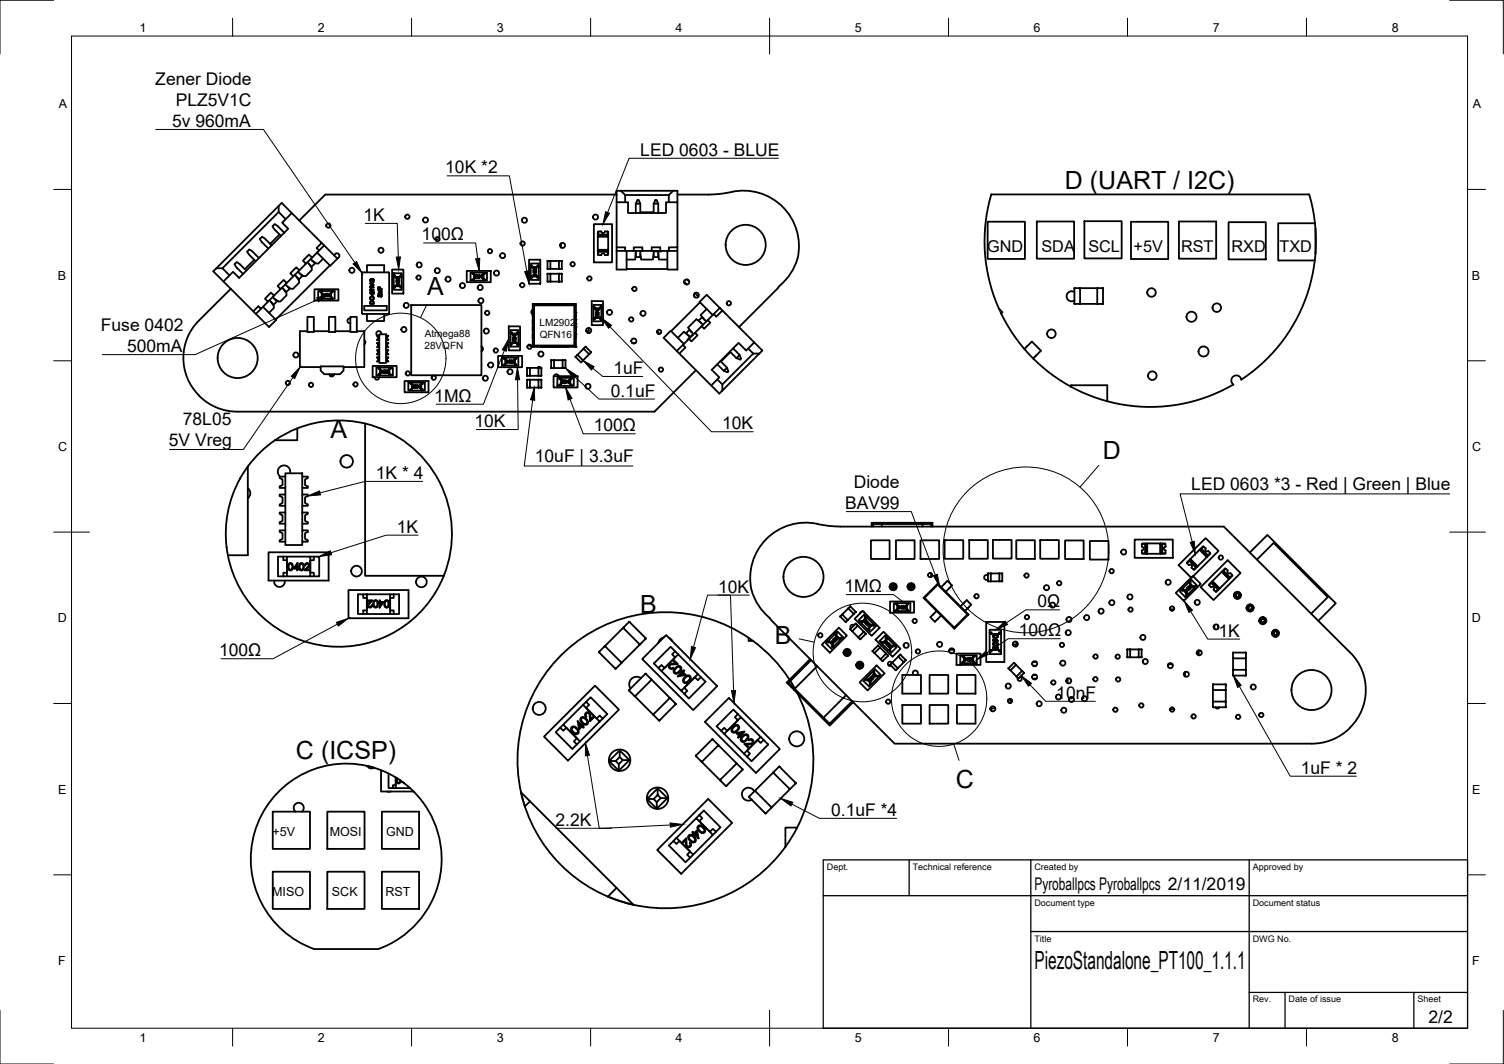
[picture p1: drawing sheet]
<svg xmlns="http://www.w3.org/2000/svg" width="420mm" height="297mm" viewBox="0 0 420 297" stroke-linecap="round" stroke-linejoin="round" font-family="sans-serif">
<defs><g id="words">
<g font-size="7">
<text x="297.5" y="52.8">D (UART / I2C)</text>
<text x="119.4" y="82.5">A</text>
<text x="92.3" y="122.4">A</text>
<text x="308.1" y="128">D</text>
<text x="178.8" y="171.2">B</text>
<text x="216.5" y="179.9">B</text>
<text x="82.7" y="212">C (ICSP)</text>
<text x="267" y="219.9">C</text>
<text x="289" y="270.6">PiezoStandalone_PT100_1.1.1</text>
</g>
<g font-size="4.9">
<text x="43.4" y="23.7">Zener Diode</text>
<text x="49.1" y="29.6">PLZ5V1C</text>
<text x="48.1" y="35.4">5v 960mA</text>
<text x="178.9" y="43.5">LED 0603 - BLUE</text>
<text x="124.4" y="48.4">10K *2</text>
<text x="101.5" y="61.7">1K</text>
<text x="117.8" y="67.1">100Ω</text>
<text x="28.2" y="92.5">Fuse 0402</text>
<text x="35.5" y="98.3">500mA</text>
<text x="171.4" y="104.4">1uF</text>
<text x="121.3" y="112.1">1MΩ</text>
<text x="170.6" y="110.7">0.1uF</text>
<text x="51.1" y="118.6">78L05</text>
<text x="132.6" y="119.2">10K</text>
<text x="201.7" y="119.8">10K</text>
<text x="47.1" y="124.4">5V Vreg</text>
<text x="165.9" y="120.4">100Ω</text>
<text x="149.4" y="129.1">10uF | 3.3uF</text>
<text x="105" y="133.7">1K * 4</text>
<text x="238.5" y="136.3">Diode</text>
<text x="332.8" y="136.8">LED 0603 *3 - Red | Green | Blue</text>
<text x="236.1" y="142.1">BAV99</text>
<text x="110.8" y="148.7">1K</text>
<text x="200.6" y="165.4">10K</text>
<text x="235.9" y="165.3">1MΩ</text>
<text x="289.9" y="169.6">0Ω</text>
<text x="284.6" y="177.6">100Ω</text>
<text x="340.4" y="177.7">1K</text>
<text x="61.2" y="183.2">100Ω</text>
<text x="295.1" y="195.1">10nF</text>
<text x="363.4" y="216">1uF * 2</text>
<text x="232.2" y="227.8">0.1uF *4</text>
<text x="155.2" y="230.5">2.2K</text>
<text x="289" y="248.5">Pyroballpcs Pyroballpcs 2/11/2019</text>
<text x="399.1" y="285.7">2/2</text>
</g>
<g font-size="4.5">
<text x="275.8" y="70.4">GND</text>
<text x="290.9" y="70.4">SDA</text>
<text x="304.1" y="70.4">SCL</text>
<text x="316.7" y="70.4">+5V</text>
<text x="329.9" y="70.4">RST</text>
<text x="344.1" y="70.4">RXD</text>
<text x="357.4" y="70.4">TXD</text>
</g>
<g font-size="3.5">
<text x="39" y="8.8">1</text>
<text x="88.8" y="8.8">2</text>
<text x="138.8" y="8.8">3</text>
<text x="188.7" y="8.8">4</text>
<text x="238.8" y="8.8">5</text>
<text x="288.7" y="8.8">6</text>
<text x="338.8" y="8.8">7</text>
<text x="388.8" y="8.8">8</text>
<text x="16.4" y="30.2">A</text>
<text x="411.4" y="30.2">A</text>
<text x="16.2" y="78">B</text>
<text x="411.2" y="78">B</text>
<text x="16.2" y="125.9">C</text>
<text x="411.2" y="125.9">C</text>
<text x="16.2" y="173.7">D</text>
<text x="411.2" y="173.7">D</text>
<text x="16.2" y="221.6">E</text>
<text x="411.2" y="221.6">E</text>
<text x="76.1" y="233.3">+5V</text>
<text x="92.1" y="233.3">MOSI</text>
<text x="107.9" y="233.3">GND</text>
<text x="76.1" y="250">MISO</text>
<text x="92.7" y="250">SCK</text>
<text x="107.7" y="250">RST</text>
<text x="16.2" y="269.4">F</text>
<text x="411.2" y="269.4">F</text>
<text x="39" y="290.8">1</text>
<text x="88.8" y="290.8">2</text>
<text x="138.8" y="290.8">3</text>
<text x="188.7" y="290.8">4</text>
<text x="238.8" y="290.8">5</text>
<text x="288.7" y="290.8">6</text>
<text x="338.8" y="290.8">7</text>
<text x="388.8" y="290.8">8</text>
</g>
<g font-size="2.8">
<text x="118.7" y="94.1">Atmega88</text>
<text x="150.7" y="91">LM2902</text>
<text x="150.8" y="94.3">QFN16</text>
<text x="118.6" y="97.4">28VQFN</text>
</g>
<g font-size="2.5">
<text x="231" y="242.9">Dept.</text>
<text x="255" y="242.9">Technical reference</text>
<text x="289" y="242.9">Created by</text>
<text x="350" y="242.9">Approved by</text>
<text x="289" y="252.8">Document type</text>
<text x="350" y="252.8">Document status</text>
<text x="289" y="262.9">Title</text>
<text x="350" y="262.9">DWG No.</text>
<text x="350" y="279.9">Rev.</text>
<text x="360" y="279.9">Date of issue</text>
<text x="396" y="279.9">Sheet</text>
</g>
</g></defs>
<!-- layer: Visible -->
<g fill="none" stroke="#000" stroke-width=".51">
<path d="M77.9 59.2l-15.8 15.7M77.9 57.5l-17.4 17.4M81.5 59.5l-2.8-2.9-.8 .9v1.7l1.9 2M172.3 56.5h3.2v3h10.6v-3h3.2v12.6h-2.5v.9M172.3 54.3h-81.4l-7.3 7.3M173.4 53.3l1.2 1.1v2.1M174.6 54.4h12.2M177.6 56.9v2.6M178.1 55.9h.3l.5 1h-1.3zM178.9 56.9v2.6M178.9 59.3h3.7M182.6 56.9v2.6"/>
<path d="M183.1 55.9h.3l.5 1h-1.3zM183.9 56.9v2.6M186.8 56.5v-2.1l1.2-1.1h1.3v3.2M188 53.3h-15.7v16.7M189.3 54.3h8.6l4.9-.4a15.5 15.5 0 0 1 15.9 3.9 15.5 15.5 0 0 1 3.5 16 15.4 15.4 0 0 1-4.4 6l-11.4 11.5M62.4 78.6l2.7-2.7 1.7 1.7 13.7-13.7-1.7-1.7 2.7-2.7 8.4 8.3-1.4 1.4 .7 .7-2 2-.9-.8-1.7 1.7 .9 .8-1.9 1.9-.8-.9-1.7 1.7 .8 .9-1.8 1.8-.9-.8-1.6 1.6 .8 .9-1.8 1.8-.9-.8-1.7 1.7 .9 .8-2 2-.7-.7-1.4 1.4M62.4 78.6l9.1 9M64.1 76.9l-2-2h-1.6l-.9 .8 2.8 2.9M68.8 75.6l-1.8-1.8-.9-.6-.6 .6 .2 .2 2.2 2.5M71 72.5l-2.6 2.6M72.3 72l-1.8-1.8-.9-.5-.5 .5 .1 .3 2.2 2.4M75.9 68.5l-2.5-2.3-.2-.1-.6 .6 .7 1 1.7 1.7"/>
<path d="M78.1 65.5l-2.6 2.6M79.4 65l-2.5-2.3-.2-.1-.6 .6 .7 1 1.7 1.7M79.7 79.4l1.2 1.2-.9 .9-1.2-1.2M80.1 79l-1.7 1.7M82.8 77.2l.8 1.2v.5l-1.7 1.7h-.6l-1.2-.8M83.2 75.9l1.3 1.2-1 .9-1.2-1.2M83.6 75.5l-1.7 1.7M86.3 73.7l.8 1.1v.6l-1.7 1.7h-.6l-1.1-.8M86.8 72.3l1.2 1.2-.9 .9-1.2-1.2M87.2 71.9l-1.7 1.7M89.9 67.8l.7 .7-1.4 1.4M90.3 72.2l-1.4 1.4h-.5l-1.2-.8"/>
<path d="M90.6 68.5l3.7 3.7-2 2-3.7-3.7M92.2 74.1l-15.2 15.1M93.4 71.3a.71 .71 0 0 1 .7-.6 .71 .71 0 0 1 .7 .7 .71 .71 0 0 1-.6 .7M101.3 76h7.2M101.3 76l-.2 .2v11.2l.2 .2h7.4v-11.4l-.2-.2M102.5 76v-2h4.8v2M103.4 79.1l1-.5-.3 .3v.5l.3 .2zM103.4 79.9l.4-.1 .7 .4-.5-.2-.1 .3-.3 .1zM103.4 78l.9-.2 .1 .7h-1zM103.5 78h.3v.3h-.3zM103.6 79.1l.4-.2v.4zM104 78h.3v.3h-.4z"/>
<path d="M109.5 75.3h3.2v6.7h-3.2zM110 77.3h2.2v2.6h-2.2zM110 76.3h2.2v.6h-.4v.4h-1.4v-.4h-.4zM110 76.9v.4M110 79.9v.4M110.7 78.7l.7-.1 .1 .2h-.1v.4zM110.8 77.5l.3-.1 .4 .4v-.4v.5l-.5-.4h-.2l.1 .4zM110.8 78.1l.5-.1 .3 .3-.7 .2zM110.8 79.3h.6l.1 .3-.6 .1zM110.9 78.8h.4v.2zM111 77.8v.1M112.2 79.9v1h-2.2v-.6h.4v-.4h1.4v.4h.4"/>
<path d="M112.2 76.9v.4M130.4 75.6h6.7v3.2h-6.7zM131.4 76.1h.6v.4h.4v1.4h-.4v.4h-.6zM132 76.1h.4M132 78.3h.4M132.4 76.1h2.6v2.2h-2.6zM132.5 76.8h.6l-.5 .5 .2 .2 .2-.2-.2 .3-.3-.3 .4-.4zM133.2 76.8h.3l.2 .2-.2 .6-.3-.2zM133.9 76.8v.2h.4l-.4 .6zM133.9 77.1h.3l-.3 .3zM134.5 76.8l.4 .1v.5l-.2 .2-.3-.2zM135 76.1h1v2.2h-.6v-.4h-.4v-1.4h.4v-.4"/>
<path d="M135 78.3h.4M147.8 72.5h3.1v6.7h-3.1zM148.3 74.6h2.2v2.6h-2.2zM148.3 73.6h2.2v.6h-.4v.4h-1.4v-.4h-.4zM148.3 74.2v.4M148.3 77.2v.4M149 76h.8h-.2v.4zM149 74.8l.3-.1 .4 .3 .1-.3v.5l-.6-.5-.1 .2 .1 .3-.1-.1zM149 75.4l.6-.1 .2 .3-.6 .2zM149 76.6l.5-.1 .3 .3-.6 .2-.2-.1zM149.2 76h.3v.3zM150.5 77.2v1h-2.2v-.6h.4v-.4h1.4v.4h.4"/>
<path d="M150.5 74.2v.4M153 78.5v.1M153 75v.1M153 76.4v.1M153 72.8v.1M153.7 76.4l.1 .1M153.7 72.8l.1 .1M153.8 76.4h2.3v2.2h-2.3zM153.8 72.9h2.3v2.2h-2.3zM153.8 76.4h-.8v2.2h.8M153.8 72.9h-.8v2.2h.8M153.8 78.5l-.1 .1"/>
<path d="M153.8 75l-.1 .1M156.1 78.5l.1 .1M156.1 75l.1 .1M156.1 78.6h.9M156.1 76.4h.9M156.1 75.1h.9M156.1 72.9h.9M156.2 76.4l-.1 .1M156.2 72.8l-.1 .1M156.8 68v1.1M156.9 76.4l.1 .1M156.9 72.8l.1 .1"/>
<path d="M157 72.9v2.2M157 76.4v2.2M157 78.5l-.1 .1M157 75l-.1 .1M165.9 62.6h5.1v10.6h-5.1zM167 69.7v.2h2.9M167 66.1v-.2h2.9v.2M167 66.1h2.9v3.6h-2.9zM167 69.9v1.2h.2M167.2 64.6h.8a.51 .51 0 0 0 .5 .5 .51 .51 0 0 0 .5-.5h.8v.9h-2.6zM167.2 64.7h-.2v1.2M168 71.2h-.8v-.9h2.6v.9h-.8"/>
<path d="M168 71.2a.5 .5 0 0 1 .5-.5 .5 .5 0 0 1 .5 .5M169.8 64.7h.1v1.2M169.9 69.9v1.2h-.1M169.9 69.7v.2M172.3 69.1h2.3v.9M172.3 70h14.5M172.3 70v5.3h2.7v-5.3M175 75.1h11.4M177 70v-.9h2.5v.9M177.6 70v1.8h1.3v-1.8M177.6 70.5l-.2 2h-2.4M178.9 70.8l.2 1.7h3.3l.2-1.7"/>
<path d="M182.1 70v-.9h2.3v.9M182.6 70v1.8h1.3v-1.6M182.8 70l1.3 .2M183.9 70.5l.1 2h2.4M184.1 70h.7M186.8 70h2.5M189.3 69.1v6.2h-2.9v-5.3M191.2 79.1l.2-.2 .5 .5M191.5 78.1l-.3 .3M192 78l.5 .6M275.9 61.9h10.4v10.4h-10.4zM289.6 61.8h10.5v10.4h-10.5z"/>
<path d="M302.9 61.8h10.5v10.3h-10.5zM316 61.9h10.3v10.4h-10.3zM329.4 61.8h10.3v10.4h-10.3zM343.2 62h10.4v10.4h-10.4zM367.3 72.7a46.4 46.4 0 0 1-20.5 33.3 1.41 1.41 0 0 0-2.2-1 1.41 1.41 0 0 0 0 2.4M367.3 62.3h-10.2v10.4h10.2M367.3 62.3l-.6-4-1-4h-88.8a46.1 46.1 0 0 0 2.1 31.8l1.1 1.1-.4 .3M367.3 62.3l.2 1.6M367.5 63.9v6.9M367.5 70.8l-.2 1.9M64.5 80.6l-9 8.9a15 15 0 0 0-3 16.3 15 15 0 0 0 13.9 9.1h116.4l11.6-11.6M72.9 86.2l-1.4 1.4"/>
<path d="M73.4 85.6l3.7 3.7-1.9 2-3.7-3.7M75.7 84.3l.8 1.1v.6l-1.3 1.3M76.2 82.9l1.2 1.2-.9 .9-1.2-1.2M76.6 82.5l-1.7 1.7M79.2 80.7l.8 1.2v.6l-1.7 1.7h-.5l-1.2-.8M83.8 92.5v9.9M83.8 92.5h2.1M83.8 92.5h.1M85.9 88.5h1.8v4.2h-1.8zM87.7 92.5h4.2M87.8 80.8h6.8v3.1h-6.8zM89.5 83.4v-.4h.4v-1.4h-.4v-.4h-.6v2.2h1"/>
<path d="M89.5 81.2h.4M89.9 81.2h2.6v2.2h-2.6zM90.1 82.1h.4l.1 .4-.3 .3-.3-.2zM91 82.2v.3h-.2zM91.1 82l.1 .6-.2 .2v-.2h-.4zM91.4 82l.4 .1-.2 .7-.4-.2zM91.9 82.8l.3-.3-.2 .2h.4zM91.9 88.5h1.8v4.2h-1.8zM91.9 82.1l.4-.1 .1 .3-.2 .2 .1-.4-.4 .1zM92.5 83.4h.4M92.5 81.2h.4M92.9 81.2h.6v2.2h-.6v-.4h-.4v-1.4h.4z"/>
<path d="M93.7 92.5h4.2M97.9 88.5h1.8v4.2h-1.8zM97.9 88.9a.71 .71 0 0 0-.9 .7 .71 .71 0 0 0 .9 .7M99.7 92.5h2M101.7 85.4h6.4v1.2h-6.4zM101.8 92.5h.1M101.8 92.5v9.9M101.8 95l.3 .5-.3 .6M102.5 87.6v2h4.8v-2M103.4 80.9h1h-.9v.2zM103.4 81.5l.4-.1 .5 .5 .1-.5v.7l-.7-.6-.2 .1 .2 .4h-.2zM103.5 84.1l.3-.1 .5 .1 .1 .7h-1z"/>
<path d="M103.6 84.2h.6l.1 .6h-.8zM104 82.2l.1 .4zM105.6 80.2l.1 .4h.3l.2-.4v.4l.5 .1h-1.1zM105.6 81.1l1.1-.2-.8 .2 .8 .4-.8 .4 .8 .2-1.1-.2 .9-.4zM105.7 82.3h.1l-.1 .3 .2 .1 .5-.5 .3 .5-.2 .2 .1-.4-.2-.2-.7 .5zM106 95.7h-.7l.3 .3v.7l-.3 .3h.7M106 93.7h-.7l.3 .3v.6l-.3 .4h.7M106 97.7h-.7l.3 .3v.6l-.3 .4h.7M106 99.7h-.7l.3 .3v.7l-.3 .3h.7M106 93.3h1.8v8h-1.8zM106.5 93.3a.71 .71 0 0 0-.9-.8 .71 .71 0 0 0-.2 1.2M107.8 93.7h.7l-.3 .3v.6l.3 .4h-.7"/>
<path d="M107.8 95.7h.7l-.3 .3v.7l.3 .3h-.7M107.8 99.7h.7l-.3 .3v.7l.3 .3h-.7M107.8 97.7h.7l-.3 .3v.6l.3 .4h-.7M114.9 85.2h19.6v19.6h-19.6zM134.5 96.7l.4 .7-.4 .6M139.1 99.4h6.8v3.1h-6.8zM140.8 99.9v.4h.4v1.3h-.4v.5M140.8 99.9h-.6v2.2h1M140.8 99.9h.4M141.2 99.9h2.6v2.2h-2.6zM142.1 91.1h3.2v6.7h-3.2zM142.6 93.2h2.2v2.6h-2.2z"/>
<path d="M142.6 96.2h.4v-.4h1.4v.4h.4v.6h-2.2zM142.6 92.8h.4v.4h1.4v-.4h.4v-.6h-2.2v1M142.6 95.8v.4M143.3 95.1l.5 .5 .2-.1-.1-.3 .2 .3-.3 .2-.4-.4-.1 .4zM143.3 94.6l.5-.1 .3 .4-.6 .1zM143.3 93.4l.5-.1 .3 .3-.6 .2zM143.5 93.9l.6 .4h-.8h.2zM143.6 94.1l.3 .2h-.3zM143.8 99.9h.4M144.8 92.8v.4M144.8 95.8v.4M147.7 96.3l.5 .4 .2-.2"/>
<path d="M148.8 84.9v11.9h12v-4.4M148.8 84.9h12l-.4 .3h-11.2M148.8 93.2v1.3M148.8 91.3v1.1M148.8 87.3v1.1M148.8 84.9l.4 .3M148.8 84.8v.1M148.8 89.2v1.3M148.8 84.8h2.4M148.8 86.5l-.4 .6 .4 .7M149.2 85.2v11.3M149.2 96.5l-.4 .3"/>
<path d="M149.2 96.5h11.2M151.2 96.8h1.2M151.2 84.8h1.2zM152.4 84.8h.8M153.2 84.8h1.2zM153.2 96.8h1.2M154.4 84.8h.8M155.2 84.8h1.2zM155.2 96.8h1.2M156.4 84.8h4.4M157.2 96.8h1.2M157.2 84.8h1.2"/>
<path d="M160.8 99.6v.1M160.8 84.9v11.9l-.4-.3v-11.3M160.8 87.3v1.1zM160.8 91.3v1.1zM160.8 93.2v1.3M160.8 84.8v2.5M160.8 88.4v2.9M161.3 99.1h.1M161.3 99l1.7-1.6 1.6 1.5-1.7 1.7zM161.3 99l-.5 .6 1.5 1.6M163.1 97.3v.1M163.6 96.8h.1"/>
<path d="M163.6 96.8l-.6 .6M163.6 96.8l1.5 1.5-.5 .6M164.2 92.9h.5M164.5 91.6v.9h-.7M164.6 98.9h.1M165.1 98.3v.1M165.3 84.1h3.2v6.7h-3.2zM165.8 89.1h.4v-.4h1.4v.4h.4v.6h-2.2zM165.8 85.7h.4v.4h1.4v-.4h.4v-.6h-2.2v1M165.8 88.7v.4M166.5 88.1l.5 .4 .2-.1-.2-.3 .2 .1 .1 .3-.4 .1-.4-.3v.3zM166.5 86.4l.5-.2 .3 .4-.7 .2z"/>
<path d="M166.5 87.6l.6-.1 .2 .3-.7 .2zM166.6 86.9l.7 .4h-.8l.1-.1zM166.7 87l.4 .2h-.4zM168 86.1h-2.2v2.6M168 86.1v2.6h-2.2M168 85.7v.4M168 88.7v.4M176.6 95.7h.9M183.6 92.4l.5 .5-.3 .3M189.8 98.7l11.2 11.2 .8-.9M190.8 96.3l.7 .7-1.7 1.7M190.8 96.3l-1.7 1.7"/>
<path d="M191.1 96l-3.7-3.7-2 2 4.4 4.4M192.5 93.9l-1.4-1.3-1.7 1.7M192.7 94.4l-.5 .5M193.7 93.4l-1.1 .9M193.8 93.3l-1.2-1.2-.9 .9 1.1 1.1M193.9 82.8l.3 .2M194.1 81.8l1 1M194.2 92.9l.7 .7-1.7 1.7-.7-.7M195.6 84.4l-8.1 8M195.9 90.1l-1.4-1-2.3 2.3 1 1.4M197.3 89.8l-1.2-1.2-.9 .9 1.2 1.2M197.4 86.3l-1.7 1.7 1.3 1.4"/>
<path d="M197.7 89.4l.7 .7-1.7 1.7-.7-.7M199.4 87.7l-8.6 8.6M201.1 86l11.9 11.9-11.2 11.1M201.1 86l-3.7-3.7-2 2 3.7 3.7M201.1 86l-1.7 1.7M201.8 86.7l-1.7 1.7-.7-.7M203.9 98.2l1.8 1.8M204 98.3l-2.6 2.6M204.8 97.3l1.8 1.8M206.6 99.1l.4 1-.2 .3-1.1-.4zM209 97.3l1.4 1.4h1.7M210.4 98.7l-8.6 8.6"/>
<path d="M210.7 95.6l-2.3 2.3-2.1-2.2-7.5 7.5 2.2 2.2-2.3 2.2M279.1 86.1l.6 1.4M279.7 87.5l2.9 5.2 3.6 4.7M286.2 97.4l2.1-2 2.5 2.5-2.2 2.2zM300.1 84.7l.2 .1M300.2 81.5a1.41 1.41 0 0 0-2.2 1.2 1.41 1.41 0 0 0 2.2 1.2M300.3 80.4l-.2 .2M301.6 80.4l.2 .2M301.7 84.8v-4.4h4.8v4.4M301.7 80.4h-1.6v4.4h8v-4.4h-1.6M301.8 84.7l-.2 .1M306.5 84.7l.2 .1"/>
<path d="M306.7 80.4l-.2 .2M308 80.4l.2 .2M308.2 84.7l-.2 .1M83.1 119.6v3.3h-6.2M83.1 119.6l-3.2 1.5-3 1.8M83.8 102.5h.1M83.8 102.5h5.8M89.6 102.3h6.4v1.2l-1 1h-4.4l-1-1zM92.1 104.5a.6 .6 0 0 0 .6 .6 .6 .6 0 0 0 .6-.6M92.1 104.8h1.1M96 102.5h5.7M101.8 102.4v.1"/>
<path d="M102 118.3v42.4h22M102 118.2a31.6 31.6 0 0 0-18.9 1.4M102 118.2a31.6 31.6 0 0 1 13.7 54.3 31.6 31.6 0 0 1-52.4-19.6M104.1 102.2h6.7v3.1h-6.7zM104.7 105.3a.6 .6 0 0 0 .6 .7 .6 .6 0 0 0 .6-.7M105.7 102.6v.4h.5v1.4h-.5v.4M106.2 102.6h-1v2.2h1M106.3 103.4l.5 .1-.2 .7-.3-.2zM107.3 103.6v.3h-.3zM107.3 103.3v.9v-.2h-.4zM107.6 103.4l.2-.1 .2 .2-.1 .7-.4-.2zM108.2 103.5h.4l-.3 .6 .3 .1h-.5l.5-.6-.3-.2-.2 .2z"/>
<path d="M108.8 102.6h-2.6v2.2h2.6M108.8 103h.4v-.4h.5v2.2h-.5v-.4h-.4zM108.8 102.6v2.2M108.8 104.8h.4M108.8 102.6h.4M113 106.4h6.7v3.1h-6.7zM114.1 106.8h.6v.4h.4v1.4h-.4v.4h-.6zM114.7 106.8h.4M114.7 109h.4M115.1 106.8h2.6v2.2h-2.6zM115.2 107.5h.5l-.4 .5 .1 .2 .3-.1-.1 .2-.4-.1 .3-.6zM115.8 107.6l.3-.1 .2 .2-.2 .6-.3-.1z"/>
<path d="M116.5 107.5l.4 .2-.4 .6zM116.5 108.3h.1M116.6 107.8h.2l-.2 .3zM117.1 107.6h.4v.5l-.2 .2-.2-.1zM117.7 106.8h1v2.2h-1M118.1 106.8v.4h-.4v1.4h.4v.4M141.4 100.6h.3l.2 .2-.2 .6-.3-.2zM142.3 100.8v.3h-.2zM142.4 100.5l.1 .7-.2 .2v-.2h-.4zM142.7 100.6h.2l.2 .2-.2 .6-.3-.2zM143.2 101.4l.4-.3-.3 .2h.4zM143.2 100.7l.5-.1-.1 .4-.1 .1 .1-.4-.4 .1z"/>
<path d="M143.8 102.1h1v-2.2h-.6v.4h-.4v1.3h.4v.5M147.2 108.1l.1 .1M147.2 104.8l.1 .1M147.2 102.7v2.2h.8M147.3 106l-.1 .1M147.3 102.7l-.1 .1M148 106l.1 .1M148 102.7h-.8M148 106h2.4v2.2h-2.4zM148 102.7h2.4v2.2h-2.4zM148 106h-.8v2.2h.8M148.1 108.1l-.1 .1"/>
<path d="M148.1 104.8l-.1 .1M150.1 102.7l.5-.3 .6 .3M150.4 108.1l.1 .1M150.4 104.8l.1 .1M150.4 108.2h.8M150.4 106h.8M150.4 104.9h.8M150.5 106l-.1 .1M150.5 102.7h.7v2.2M151.2 106l.1 .1M151.2 102.7l.1 .1M151.2 106v2.2"/>
<path d="M151.3 108.1l-.1 .1M151.3 104.8l-.1 .1M154 102.7v.1M154 100.5v2.3h.8M154 100.5h.8M154 100.5v.1M154.6 105h6.8v3.2h-6.8zM154.7 100.5l.1 .1M154.8 100.5h2.4v2.3h-2.4zM154.8 102.7l-.1 .1M155.7 105.5h.6v.4h.4v1.4h-.4v.4h-.6zM156.1 105a.71 .71 0 0 0-.7-.5 .71 .71 0 0 0-.7 .5"/>
<path d="M156.3 107.7h.4M156.3 105.5h.4M156.7 105.5h2.6v2.2h-2.6zM156.8 106.2h.5l-.4 .5 .1 .2 .3-.2-.2 .3-.3-.3 .4-.5zM157.2 102.7v.1M157.2 100.5h.8M157.5 106.2l.2-.1 .2 .2-.1 .7-.4-.2zM157.9 100.5l.1 .1M158 100.5v2.3h-.8M158 102.7l-.1 .1M158.1 106.2l.1 .1h.4l-.5 .7zM158.2 106.4h.2l-.2 .4z"/>
<path d="M158.7 106.2h.3l.2 .2-.2 .6-.3-.2zM159.3 105.5h1v2.2h-.6v-.4h-.4v-1.4h.4v-.4M159.3 107.7h.4M162.3 101.1h.1M162.9 100.5l-.6 .7M200.4 101.7l1.8 1.8M200.4 105.9l1.4 1.4v1.7M201.3 100.8l1.8 1.8M202.2 103.5l.9-.9 .4 1.1-.3 .2zM288.6 100.1l4.3 3.7 3 2.2 3.3 2M299.2 108l4.9 2.3 5.2 1.7M299.2 108v-.4h10.1v4.4"/>
<path d="M344.6 107.4a46.2 46.2 0 0 1-35.3 4.6M67 133.6a31.5 31.5 0 0 0-3.7 19.3M69.2 130.2v24.7M69.2 130.2l-2.1 3.5M69.3 136.3a1.75 1.75 0 0 1 0 2.8M76.9 122.9a31.6 31.6 0 0 0-7.7 7.3M79.7 138.1h-1.6v.4l.8 .4v1.5l-.8 .4v.4h1.6M79.7 133.1h-1.6v.4l.8 .3v1.6l-.8 .4v.4h1.6M79.7 132.1h4.7v20.1h-4.7zM81 132.1a1.75 1.75 0 0 0-2.2-2.1 1.75 1.75 0 0 0-.5 3.1M84.4 133.1h1.6v.4l-.8 .3v1.6l.8 .4v.4h-1.6M84.4 138.1h1.6v.4l-.8 .4v1.5l.8 .4v.4h-1.6"/>
<path d="M63.6 155h5.6M69.3 154.9l-.1 .1M75 154.2h16.8v7.9h-16.8zM79.2 155.4v1h1v3.5h-1v1M79.7 143.1h-1.6v.4l.8 .4v1.5l-.8 .4v.4h1.6M79.7 148.1h-1.6v.4l.8 .4v1.5l-.8 .4v.4h1.6M80.2 155.4h6.5v5.5h-6.5zM80.2 155.4h-2.5v5.5h2.5M80.7 157.3l.6-.1 .5 .5v1.1l-.5 .4h-.5l-.3-.5v-.9zM80.8 157.5l.4-.1 .4 .3v.9l-.3 .5-.6-.4zM83 157.7v.9h-.6zM83.1 157.2v1.4h.3v.2h-.3v.4h-.1v-.4h-1z"/>
<path d="M83.8 157.4l.6-.2 .4 .5v1.1l-.4 .4h-.6l-.2-.4zM83.9 157.5l.4-.1 .4 .3v.8l-.3 .6-.4-.1-.2-.4zM84.4 148.1h1.6v.4l-.8 .4v1.5l.8 .4v.4h-1.6M84.4 143.1h1.6v.4l-.8 .4v1.5l.8 .4v.4h-1.6M85.3 157.4l.6-.2 .5 .3-.1 .7-.8 .8h.9v.2h-1.3l1.1-1.3-.3-.5-.7 .4zM86.7 156.4h1v-1h1.5v5.5h-1.5v-1h-1zM86.7 155.4h1M228.3 146.3l3.3 .5 3.2 .2h107.1l35.3 35.2a14.8 14.8 0 0 1-.2 21.1M228.4 146.3a15.3 15.3 0 0 0-17.5 21l2.1 3.2 2 2M243.3 150.8h5.2v5.2h-5.2zM243.9 147v-.7h16.2v.7M246.3 146h-2.8v1"/>
<path d="M246.3 146v1M246.3 146h14.2v1M250.3 150.8h5.2v5.2h-5.2zM257.2 150.8h5.2v5.2h-5.2zM257.7 146v1M263.9 150.8h5.2v5.2h-5.2zM270.8 150.8h5.1v5.2h-5.1zM277.4 150.7h5.2v5.2h-5.2zM283.9 150.8h5.2v5.2h-5.2zM290.6 150.8h5.2v5.2h-5.2zM297.5 150.9h5.2v5.2h-5.2zM304.5 151h5.2v5.2h-5.2z"/>
<path d="M317 150.6h10.6v5.1h-10.6zM319 151.9h.9v2.6h-.9v-.9a.5 .5 0 0 0 .5-.5 .5 .5 0 0 0-.5-.5zM319.1 154.5v.1h1.2M320.3 151.7h-1.2v.2M320.5 151.7h-.2v2.9h.2M320.5 151.7h3.6v2.9h-3.6zM324.1 151.7h.2M324.3 151.7v2.9h-.2M324.3 151.7h1.2v.2M324.7 151.9h.9v.7a.5 .5 0 0 0-.5 .5 .5 .5 0 0 0 .5 .5v.9h-.9zM325.5 154.5v.1h-1.2M329.2 157.8l7.6-7.6 3.6 3.6-7.6 7.6z"/>
<path d="M331.6 157.2l.6-.6 1.9 1.8-.7 .7-.5-.6a.5 .5 0 0 0 0-.7 .5 .5 0 0 0-.7 0zM332.4 156.2l-.8 .8 .1 .1M332.5 156l-.1 .2 2.1 2M332.5 156l2.6-2.5 2 2-2.5 2.6zM334.5 158.2l-.9 .9-.1-.1M334.6 158.1l-.1 .1M335.1 153.5l.1-.1 2.1 2-.2 .1M336.2 152.6l-.1-.1-.9 .9M337.5 153.8a.5 .5 0 0 1-.7 0 .5 .5 0 0 1 0-.7l-.5-.5-.7 .6 1.9 1.8 .6-.6-.6-.6M338 154.5l.1 .1-.8 .8M341.3 159.6l.1-.1 2.1 2.1-.2 .1M341.3 159.6l2 2.1-2.6 2.6"/>
<path d="M341.3 159.6l-2.6 2.6 2 2.1M342.3 158.8l-.1-.1-.8 .8M343 156.4l3.6 3.6-7.6 7.5-3.6-3.6zM343.7 160a.5 .5 0 0 1-.7 0 .5 .5 0 0 1 0-.7l-.6-.6-.6 .6 1.8 1.9 .7-.6-.6-.6M349.1 154.2l5-4.9 19.1 19.1-4.9 4.9M355.8 151.6l15.1 15.1M356 151.3l-4.9 4.9M76.6 162.1a1.49 1.49 0 0 0 1.5 1.8 1.49 1.49 0 0 0 1.4-1.8M86.7 160.9h1M97.3 164.7h16.8v7.9h-16.8zM100 165.9h1.5v1h1v3.5h-1v1h-1.5zM101.5 165.9h1"/>
<path d="M101.5 171.4h1M102.5 165.9h6.5v5.5h-6.5zM102.7 167.6h1.4l-1.2 1.3 .4 .5 .7-.4-.4 .6h-.6l-.3-.6 .9-1.2h-.9zM104.4 167.8l.6-.3 .6 .5v1.1l-.5 .5h-.4l-.4-.4-.1-.8zM104.6 167.9l.5-.1 .3 .3v.8l-.3 .5h-.4l-.2-.3zM106 167.6h.2v.4h.9l-1.1 1.6v-1.4h-.2v-.2h.2zM106.2 168.2h.6l-.6 .9zM107.6 167.7l.6-.1 .4 .4v1.2l-.4 .4-.5-.1-.3-.4-.1-.9zM107.7 167.9l.4-.2 .4 .4v1l-.4 .3-.4-.1-.2-.4zM109 165.9h2.5v5.5h-1.5v-1h-1v-3.5h1v-1M109 171.4h1M174.1 175.3l4.7 4.6-5.1 5.1-4.7-4.6z"/>
<path d="M174.2 175.1v.3M175.6 173.7l.2-.1 4.6 4.6-.1 .2M175.6 173.7l-1.5 1.6M175.7 173.7h.2M178.6 179.8h.3M180.3 178.4l-1.5 1.5M180.3 178.1v.3M185.5 177.9a2.11 2.11 0 0 0-1.6 1.6M186.9 178.1l.9 .9M209.1 178.1v.8h1.3M210.4 178.9a41.3 41.3 0 0 0-47.1-1.3 41.3 41.3 0 0 0-17.8 43.5M210.4 178.9a41.3 41.3 0 0 1 12.3 52.1"/>
<path d="M215 172.5l34.9 35.1h116.5a15 15 0 0 0 10.6-4.3M229.6 180l4.8-4.8 2.2 2.2-4.8 4.8zM231.1 179.1l.3 .3 .3-.3 1 1-.3 .3 .3 .3M231.1 179.1l-.4 .5 1.5 1.5 .5-.4M231.4 178.9l-.3 .2M232.2 179.1l.6 .2-.1 .4-.4-.1zM232.7 178.5l.6 .4v.3l-.2-.2-.2 .3zM232.8 178.7l.3 .3-.2 .1zM233 178.2l.5 .1 .2 .5h-.4l-.3-.3zM233.5 177.8h.4v.6l.4-.2-.4 .3-.1-.6-.2-.1-.1 .3zM233.5 176.7l.4-.4 1.6 1.6-.4 .4-.3-.3-.3 .3-1-1 .3-.3zM233.5 176.7l-.3 .3"/>
<path d="M234.7 172.1l1.6 1.5M234.8 172.1h-.1M234.8 172.1v.1M234.8 178.6l-1.6-1.6-1.8 1.9 1.6 1.5M234.8 178.6l-1.8 1.8M235.1 178.3l-.3 .3M235.2 171.6l-.4 .5M235.2 171.6h.1M235.3 171.5l1.7-1.7 1.5 1.6-1.7 1.7zM235.3 171.5l-.1 .1M236.2 173.6h.1M236.8 173l-.5 .6"/>
<path d="M237 169.8h.1M237 169.8v.1M237.5 169.3l1.6 1.6M237.5 169.3l-.5 .5M237.5 169.3h.1M237.6 175.6l.5 .6M237.6 175.6v.1M238 176.2h.1M238.1 176.2l1.5-1.5 1.7 1.7-1.5 1.5zM238.5 171.4h.1M238.6 171.4h-.1M238.7 174.5a.71 .71 0 0 0-1 .1 .71 .71 0 0 0 0 .9"/>
<path d="M238.8 172.7l2.2-2.2 4.7 4.8-2.2 2.2zM239 174.1h.1M239.1 170.8v.1M239.1 170.9l-.5 .5M239.6 174.6v.1M239.6 174.7l-.5-.6-1.5 1.5M239.8 177.9v.1M239.8 178l.6 .4M240.3 173.6l.2 .3M240.3 178.4h.1M240.5 173.9l1.6-1.6 1.8 1.8-1.5 1.6zM240.8 170.7l-.6 .6"/>
<path d="M241.3 170.8l.3 .3M241.3 176.4h.1M241.3 176.4l.6 .6M241.4 171.6l.4 .4-.3 .3 .3 .3-1 1-.3-.3-.2 .3-.5-.4zM241.7 172.9l.4 .3-.7 .1-.1 .2 .4 .1-.4 .1v-.5h.6zM241.8 173.6l.5-.2 .1 .3-.6 .4-.1-.2zM241.8 172l.3 .3M241.8 176.9v.1M241.9 177l-1.5 1.4M242.2 174.3l.3-.3 .2 .2zM242.4 175.7l.3 .3M242.4 173.8h.2l-.1 .2 .3 .2-.7 .2z"/>
<path d="M242.7 174.5l.4-.2 .2 .3-.6 .4zM243.9 174.1l.7 .8-1.5 1.5-.4-.4M244.2 174.4l-.3 .3-.3-.3-.9 1 .3 .3-.3 .3M244.6 178.6l2.2-2.2 4.8 4.7-2.3 2.3zM246.4 179.7l1.5-1.5 1.9 1.8-1.6 1.6zM247.3 179l.2-.1 .3 .2-.5 .5-.3-.2zM247.5 179.6l.8-.1-.6 .6 .1-.2zM247.6 179.7l.5-.1-.3 .2zM247.6 177.9l-.2 .3 .2 .2-.9 1-.3-.3-.3 .3M247.9 178.2l-.7-.8-1.5 1.6 .7 .7M248.1 179.9l.4-.1 .1 .3-.6 .4-.1-.3zM248.6 167.9h6.8v3.2h-6.8z"/>
<path d="M248.9 163.1l.4 .4v.5l-.4 .5zM248.9 163.1h1.2M249.3 164h.4l.4 .5h-1.2M249.3 163.5h.4M250.1 163.1l-.4 .4v.5M250.1 163.1v1.4M250.3 170.6v-.4h.4v-1.4h-.4v-.4h-.6v2.2h1M250.3 168.4h.4M250.7 168.4h2.6v2.2h-2.6zM250.9 169.2h.4l-.1 .7-.3-.1zM251.8 169.3v.4h-.2zM251.9 169.1h.1"/>
<path d="M251.9 169.1l.1 .6-.2 .2v-.2h-.4zM252.1 169.2h.4v.7l-.4-.1zM252.8 169.2h.4l-.4 .6 .4 .1h-.5l.4-.5-.1-.2-.3 .2zM253.3 168.8h.4v-.4h.6v2.2h-.6v-.4h-.4zM253.3 170.6h.4M253.3 168.4h.4M253.9 163.1l.4 .4v.5l-.4 .5zM253.9 163.1h1.2M253.9 164.5h1.2M254.3 164h.4v-.5l.4-.4v1.4l-.4-.5M254.3 163.5h.4M258 166.9l8.6 8.6"/>
<path d="M258.3 166.9l8.3 8.3M260.1 160v1.1M261.7 170.6l-1.8 1.7 1.3 1.3 1.7-1.8M262 162.9l8.6 8.6M262 162.9l-4 4h.3M262 163.2l8.3 8.3M262 163.2l-3.7 3.7M262 162.9v.3M262.9 163.9l1.8-1.7 1.3 1.2-1.8 1.8M266.6 175.2l3.7-3.7h.3l-4 4zM268.3 169.3l1.8-1.8 1.2 1.3-1.7 1.8M275.5 173.6h5.1v11.2h-5.1z"/>
<path d="M276 162.2l.1 .1M276 160.6a.71 .71 0 0 0-1.1 .6 .71 .71 0 0 0 1.1 .6M276.1 160.1h-.1M276.5 177h3.2v4.4h-3.2zM276.5 176.5h.6v.5h2v-.5h.6v-.7h-3.2v1.2M276.8 162.2l-.1 .1M276.8 160.1h-.8v2.2h.8M277.5 179.5l.4-.2 .6 .1 .3 .5-.3 .3h-.8l-.3-.3zM277.5 177.4l.9-.2 .4 .2v.4l-.4 .3h-.6l-.4-.3zM277.5 178.4l.4-.1 .9 .6-.6-.3-.1 .4-.4 .2-.3-.4zM277.6 179.6l.8-.1 .3 .3-.3 .3h-.6l-.3-.2zM277.6 177.4l.9-.1 .2 .4-.3 .3h-.6l-.3-.3z"/>
<path d="M279.2 160.1h-2.4v2.2M279.2 160.1v2.2h-2.4M279.2 160.1h.8v2.2h-.8M279.2 162.2l.1 .1M279.3 160.1h-.1M279.7 176.5v.5M279.9 160.1h.1M280 162.2l-.1 .1M283.9 179.2v1.3v-.6h-1M326.9 170.1h1.1M327.2 170.5h.4M328.5 165.5l4.7-4.7 2.2 2.2-4.7 4.8z"/>
<path d="M329.6 165.1l.4-.4 .3 .3 .2-.3 1 1-.2 .3 .2 .3-.4 .4zM330.3 164.4l-.3 .3M331 164.7h.5l.2 .5h-.4zM331.1 164.7h.3l.2 .4-.3 .1zM331.6 164.1l.5 .6-.1-.1-.3 .3zM331.7 164.3l.3 .2-.2 .2zM331.8 166l-.3 .3M331.9 163.8h.4l.2 .5h-.5zM332.1 162.6l-1.8 1.8 1.5 1.6 1.9-1.9M332.1 162.6l1.6 1.5M332.4 163.3l.3 .1 .1 .5 .3-.2-.4 .4v-.7h-.3v.3zM332.4 162.3l-.3 .3"/>
<path d="M332.8 161.9l1.6 1.5-.5 .5-.2-.3-.3 .3-1-1 .3-.3-.3-.3zM333.9 163.9l-.2 .2M337.8 163.4l.6-.7 1.8 1.9-.6 .6-.6-.6a.5 .5 0 0 0 0-.7 .5 .5 0 0 0-.7 0zM338.6 162.4l-.9 .8 .1 .1M338.7 162.2l-.1 .2 2 2M339.3 174.5v1.1M340.3 174.6v.9M340.6 164.4l-.8 .9-.1-.2M340.7 164.3l-.1 .1M344.2 160.6l.1 .1-.8 .9M344.8 166.2l.3 .1M344.8 166.2l.9 .9"/>
<path d="M345.7 166.8v.3M345.8 165.2v.3M345.8 165.2l.9 .9M345.8 165.2l-1 1M345.8 165.5l.6 .6-.7 .7M345.8 165.5l-.7 .8 .6 .5M346.4 166.1h.3M346.7 166.1l-1 1M348.3 169.7l.3 .1M349.2 170.3v.4M349.3 168.8v.3M349.3 168.8l-1 .9 .9 1 1-1"/>
<path d="M349.3 168.8l.9 .9M349.3 169.1l.6 .5-.7 .7M349.3 169.1l-.7 .7 .6 .5M349.9 169.6l.3 .1M351.8 173.3h.3M352.7 173.9v.3M352.8 172.3l.1 .3M352.8 172.3l-1 1 .9 .9 1-1M352.8 172.3l.9 .9M352.9 172.6l.5 .6-.7 .7M352.9 172.6l-.8 .7 .6 .6M353.4 173.2h.3"/>
<path d="M355.4 176.8l.3 .1M355.4 176.8l.9 .9M356.3 177.4v.3M356.4 175.8v.3M356.4 175.8l.9 .9M356.4 175.8l-1 1M356.4 176.1l.6 .6-.7 .7M356.4 176.1l-.7 .8 .6 .5M357 176.7h.3M357.3 176.7l-1 1M371.2 166.5l-4.9 4.8M163.6 199.1l.4-.3 .8 .3 .2 1.7 .8-.7 .1 .1-1.1 1.2-.2-2.1-.4-.3-.3 .1-.2 .4 .1 .5-.1 .1-.3-.4z"/>
<path d="M163.7 195.9l-.8 .9M167.4 181.9v.3M167.4 181.9l-.1 .2 4.5 4.5M168.8 180.5l-1.4 1.4M168.9 180.5h.2M169 180.4l-.2 .1M171.8 186.6h.3M173.5 185.2l-1.4 1.4M173.6 184.9v.3M173.7 185l-.2 .2M175.8 192.6v.2M175.8 192.6l-.1 .1 1.5 1.6"/>
<path d="M177.2 194.3l.2 .1M177.2 194.3h.3M179.1 189.3a2.11 2.11 0 0 0-2.7 .2 2.11 2.11 0 0 0-.2 2.7M179.4 184l6.7-6.7 14.2 14.2-6.6 6.7zM180.2 188.2h.3M181.9 189.6v.3M182 189.7l5.1 5.1-4.6 4.7-5.1-5.1zM182 189.7l-1.7-1.6-4.5 4.5M182.5 199.5l.1 .1M182.6 199.4v.2M182.6 199.6l1.4 1.5M182.7 185.2l4.6-4.6 1.3 1.2-.8 .9 .8 .8-3 3-.8-.9-.9 .9z"/>
<path d="M183.9 186.5l.9 .9M187 194.9h.3M187.1 194.8l1.7 1.7-.1 .2M188.1 184.5l.1-.2 1.2 1.1-2.2 .2-.2 .3 .2 .5 1 .1-.8 .3-.5-.5v-.7l.5-.3 1.4-.1zM188.6 186.5l.6-.5 .6-.1 .4 .3 .2 .6-.7 .9-1 .4-.5-.6zM188.6 181.8l.9 .9M188.7 196.7l-4.4 4.4M188.7 196.4v.3M188.7 186.7l.8-.6 .4 .1 .2 .4-.3 .8-.8 .5-.6-.4zM189.5 182.7l5.5 5.5-4.7 4.7-5.5-5.5zM189.9 188.5l.7-.7 .5 .5zM190.3 187.5l.2-.2 .1 .2 .5-.4 .1 .1-.4 .4 .8 .8-2.3 .4 1.2-1.2z"/>
<path d="M190.3 192.9l.9 .8M191.2 192l2.9-3 .9 .9 .8-.9 1.3 1.3-4.7 4.7-1.2-1.3 .8-.8zM191.2 189.1l1.1-.6 .5 .3 .2 .5-.6 1-.9 .4-.4-.1-.3-.5 .1-.5zM191.4 189.3l.8-.5 .5 .2v.4l-.6 .9-.7 .2-.4-.4zM195 188.2l.8 .8M206.1 199.4l.9 .8M221.8 192.5l8 8.1M226.3 184l-6.5 6.5 2 2M226.6 184.3l-6.3 6.3 11.5 11.4 6.3-6.3M228.3 186l-6.5 6.5M233 180.4l-.3 .3M235.7 182.2h.6"/>
<path d="M235.7 182.2l.9 .9M236.3 182.2l.3 .3M236.4 194l-6.6 6.6M236.6 181.9v-.6l1 .8M236.6 181.9l-.3 .3M236.6 181.3l-.9 .9M236.6 181.9l.3 .2M236.9 182.1l-.3 .4v.6M236.9 182.1h.7M237.6 182.1l-1 1M238.3 196l-6.5 6.6-2-2M239.2 185.8l.9 .9"/>
<path d="M239.8 185.8l.3 .3M240.1 186.1l.4-.4h.6l-1 1M240.1 186.1v.6M240.1 190.5l4.8-4.7 2.2 2.2-4.7 4.8zM240.2 185.4l-.4 .4h-.6M240.2 184.8l-1 1M240.2 185.4l.3 .3M240.2 184.8v.6M240.2 184.8l.9 .9M241.9 189.4l-.7 .7 1.6 1.6 .4-.5-.3-.2 .3-.3-1-1-.3 .3-.2-.3M242.5 189.8l.3-.4v.5v-.3zM242.9 189.9l.2 .3 .1-.4 .1 .4h-.4z"/>
<path d="M243.1 189.2h.4l.2 .5h-.5zM243.4 188.9l.5-.2 .1 .7zM243.5 191l-.3 .2M243.7 181.8l.6 .5M243.8 187.6l1.5 1.5-1.8 1.9-1.6-1.6zM243.8 181.7l-.1 .1M243.8 181.7v.1M243.8 188.8l.1 .5-.3-.3zM243.9 188.3h.4l.3 .5-.4 .1zM244.1 187.3l.4-.5 1.5 1.6-.4 .4-.3-.3-.3 .3-.9-1 .2-.2zM244.1 187.3l-.3 .3M244.2 182.3h.1"/>
<path d="M244.3 182.3l1.6-1.5 1.6 1.7-1.5 1.5zM245.2 180.2h.1M245.6 188.8l-.3 .3M245.8 180.7v.1M245.9 180.8l-.6-.6-1.5 1.5M246 184l.6 .5M246 184v.1M246.5 184.5h.1M247.6 182.5l.5 .6M248.1 183v.1M248.1 183.1l-1.5 1.4M248.2 181.6l.3 .2"/>
<path d="M248.2 180.6h.8l-.2-.4 .3 .2-.2 .3h-.5l.2 .3zM248.5 181.3l1-1 .3 .3 .3-.3 .4 .4-1.6 1.6-.4-.5 .3-.2zM248.7 185.6l1.6 1.5M248.7 185.5v.1M249.2 185.1a.6 .6 0 0 0-.8-.3 .6 .6 0 0 0-.3 .8 .6 .6 0 0 0 .9 .2M249.2 185l-.5 .5M249.2 185h.1M249.2 185l1.8-1.7 1.5 1.6-1.7 1.7zM249.8 180l.3 .3M250.2 187.1h.1M250.8 186.6l-.5 .5M250.8 186.5v.1"/>
<path d="M250.8 186.6h.1M251 183.3h.1M251 183.2v.2M251.5 182.8l-.5 .5M251.5 182.8h.1M251.5 182.7l1.5 1.6M251.5 182.7v.1M252.1 188.4h5.2v5.2h-5.2zM252.1 196.8h5.2v5.2h-5.2zM252.5 184.8h.1M252.5 184.8v.1M253 184.2v.1"/>
<path d="M253 184.3l-.5 .5M255.2 188.4a.71 .71 0 0 1 0-1 .71 .71 0 0 1 1 0 .71 .71 0 0 1 0 1M259.7 188.4h5.2v5.2h-5.2zM259.7 196.8h5.2v5.2h-5.2zM265.2 181.4h1.3M267.2 182.5h6.7v3.1h-6.7zM267.3 188.4h5.2v5.2h-5.2zM267.3 196.8h5.2v5.2h-5.2zM268.1 185.6h.5M268.9 185.2v-.5h.4v-1.3h-.4v-.4h-.6v2.2h4M268.9 183h.4M269.3 185.2v-2.2h2.6v2.2"/>
<path d="M269.5 183.7h.3l.1 .2-.2 .6-.3-.2zM270.4 183.9v.3h-.3zM270.4 183.7v.8v-.2h-.4zM270.7 183.7h.3l.1 .2-.1 .6-.4-.2zM271.3 183.8h.4l-.3 .6 .4 .1h-.6l.5-.6-.2-.2-.2 .2zM271.9 183.4h.4v-.4h.6v2.2h-.6v-.5h-.4zM271.9 183h.4M276.5 181.9h.6v-.5h2v.5h.6v.7h-3.2zM276.5 181.4v.5M276.7 197.7h1.3M276.7 198.2h.4v.3M277.5 180.6l.3-.2-.3 .3 .3 .5 .3-.4 .2 .3h.3l-.1-.7 .3 .3v.3l-.2 .2-.4-.1-.5 .2-.3-.3z"/>
<path d="M279.7 181.4v.5M281.6 195.4h1.1h-.4v.8M281.7 186.6h.1M281.7 186.6l.5 .5M281.7 186.5v.1M281.8 186.5v.1M282.2 187.1h.1M282.3 187.1l1.5-1.5 1.7 1.7-1.5 1.6zM283.2 185.1l-1.5 1.4M283.2 185.1h.1M283.3 185.1l.5 .5M284 188.9h.1"/>
<path d="M284 188.9l.5 .5M284 188.8v.1M284.5 189.4h.1M285 188.9a.6 .6 0 0 1 .4 .8 .6 .6 0 0 1-.8 .3 .6 .6 0 0 1-.3-.8M285.6 187.3h.1M285.6 187.3l.4 .5M286 187.8l.1 .1M286.1 187.8v.1M286.1 187.9l-1.6 1.5M288.5 189.4h1.1M288.5 184.9h1.1M288.6 188.5h.9"/>
<path d="M288.6 185.9h.9M298.3 189.4v1.3M314.9 183.4l.1 .1M315 181.3l-.1 .1M315.7 181.3v.1M315.7 181.3h2.4v2.2h-2.4zM315.7 181.3h-.8v2.2h.8M315.7 183.4v.1M318.1 183.4l.1 .1M318.1 181.3h.8M318.1 183.5h.8M318.2 181.3l-.1 .1"/>
<path d="M318.9 181.3v.1M318.9 181.3v2.2M318.9 183.4v.1M326.4 185.4h1.1M326.9 198h1.1M327.3 197.5h.3M331 187.7v1.1M331 187.6v1.2M334.9 181.6v1.3M334.9 181.7h.5M338.8 192.6h3.6v3.3h-3.6zM338.8 192.6v-1.5h3.6v1.5"/>
<path d="M338.8 195.9v1.5h3.6v-1.5M338.8 197.3l.2 .1M338.8 192.5l.2 .1M339 195.8l-.2 .2M339 191l-.2 .2M339.6 197.5l.5 .3 .6-.3M342.3 195.8l.2 .2M342.3 191l.2 .2M342.5 197.3l-.2 .1M342.5 192.5l-.2 .1M344.5 188.5l.1 .1M344.5 183.7l.1 .1"/>
<path d="M344.5 183.8h3.6v3.2h-3.6zM344.5 183.8v-1.6h3.6v1.6M344.5 187v1.6h3.6v-1.6M344.6 187l-.1 .1M344.6 182.2l-.1 .1M347.9 187l.2 .1M347.9 182.2l.2 .1M348.1 188.5l-.2 .1M348.1 183.7l-.2 .1M102.5 213.8a1.41 1.41 0 0 0 2 .5M104.5 214.3a26.7 26.7 0 0 0-33.1 17.2 26.7 26.7 0 0 0 16.3 33.4M104.5 214.3l1.9 .7"/>
<path d="M106.4 215l2.2 .9M106.4 215v6h9.1M108.5 215.9v4.1h1.2v-.8h.9v-2.1M108.6 215.9l2 1.1M110.6 217.1v2.9h4M110.6 217l.3 .3M110.9 217.3l-.1 .7 .2 .6h.7l.2-.7M110.9 217.3l.2 .1M111.1 217.4l.6 .4M111.1 217.4l-.2 .6 .3 .5 .4-.1 .1-.6M111.7 217.8l.2 .1M111.9 217.9l.3 .2"/>
<path d="M112.2 218.1l-.2 .2h.5M112.2 218.1l.3 .2M112.5 218.3l.4 .4M112.8 218.6l.1 .1M112.9 218.7l1.6 1.3M152 205.6l14.2-14.2 6.7 6.7-14.2 14.2zM155.2 204.4l1.3-1.3 .9 .9 .8-.9 3 3-.9 .9 .9 .8-1.3 1.3zM157.4 202.3l5.5-5.5 4.6 4.7-5.5 5.5zM157.4 202.3l-.9 .8M159.6 203.1l.7-.3 .7 .3 .6 .9-.1 .7-.6 .3-.7-.4-.7-.8zM159.9 203.1h.6l.7 .5 .3 .5-.2 .5-.5 .1-.7-.5-.4-.6zM161.4 201.3l1.2 1.2 .2-.2 .1 .1-.2 .2 .4 .4-.1 .2-.4-.4-.8 .8z"/>
<path d="M161.7 201.9l.7 .7-.5 .5zM162 207l-.8 .8M162.3 200.4l.6-.2 .7 .3 .7 .9-.1 .7-.7 .3-.8-.5-.6-.7zM162.5 200.5l.5-.1 .6 .4 .4 .6v.6l-.5 .1-.6-.3-.5-.7zM168.4 200.6l-.9-.8-.8 .8-3-3 .9-.8-.9-.9 1.3-1.2 4.7 4.6-2.2 2.2M170.2 212.5l2.7 2.7M172 212.5l.9 .8M172.9 213.3l1.1-1.1h1.8l-2.9 3M172.9 213.3v1.9M173.1 209.5l-2.9 3h1.8l1.1-1.2 .9 .9M173.1 211.3v-1.8l2.7 2.7M184 201.1h.3"/>
<path d="M194.5 211.1l1.4 1.5M194.5 210.8v.3M195.9 212.6l.1 .1M195.9 212.6h.3M196.9 201.5l6.7-6.7 14.3 14.3-6.7 6.7zM198.9 206.5h.3M199.2 206.5l-.2-.2-4.6 4.7 .1 .1M199.2 206.5l1.4 1.4M200.6 207.9l.1 .1M200.6 207.9v.3M200.7 208l5.1 5.1-4.7 4.7-5.1-5.1zM201.1 217.8l1.6 1.6"/>
<path d="M201.3 217.6v.3M201.5 204l.8-.8 .9 .8 2.9-2.9-.8-.9 .8-.8-1.2-1.3-4.7 4.7 2.1 2.1M202.3 204.9l4.7-4.7 5.5 5.5-4.7 4.7zM202.7 219.4h.3M204.9 202.8l.9-.5 .4 .2 .3 .5-.2 .7-1.1 .8-.6-.1-.3-.4 .1-.6zM204.9 203.1l.7-.5h.4l.3 .4-.3 .8-.8 .5-.5-.1-.2-.3zM205.7 213.3h.3M205.7 204.6l2.3-.4-1.2 1.2 .2 .2-.2 .2-.2-.2-.4 .4-.1-.2 .4-.3zM205.8 213.1l1.6 1.6M206.1 204.8l1.3-.3-.7 .8zM207.4 214.7l.1 .1-4.7 4.7-.1-.1M207.4 214.7v.3"/>
<path d="M207.6 205.3l.9-.3 .6 .5-.4 1-1 .7-.5-.2-.3-.5 .1-.5zM207.6 205.6l.8-.4 .4 .2 .1 .4-.5 .8-.8 .3-.3-.1-.1-.5zM207.8 210.4l.9 .9M207.9 207.7l2.2-.3v-.6l-.3-.3-.5 .2-.2-.2 .3-.2h.6l.5 .5-.1 .5-.3 .4-1.7 .1 .8 .8-.2 .2zM211.6 206.6l.9 .8 .8-.8 1.3 1.2-4.6 4.7-1.3-1.2 .8-.9-.8-.8zM212.5 205.7l.8 .9M216 215.7l4.7 4.6-5.1 5.1-4.7-4.6zM216 215.7l1.7-1.7 4.7 4.6-1.7 1.7M216.1 215.5v.3M217.6 214.1h.3M222.2 218.5v.3M76.2 226.6h10.4v10.4h-10.4z"/>
<path d="M82.5 226.6a1.41 1.41 0 0 1-.1-2 1.41 1.41 0 0 1 2.1 0 1.41 1.41 0 0 1-.1 2M91.4 226.6h10.4v10.4h-10.4zM106.7 226.6h10.4v10.4h-10.4zM108.2 221h1M109.7 220h.9M114.5 220a26.7 26.7 0 0 1-8.8 44.9M145.5 221.2l31.5 31.4M145.5 221.1l1.1 4M145.5 221.1a41.3 41.3 0 0 0 31.5 31.5M148.1 223.7l-1.5 1.4M180.8 223.1l2.7 2.7M182.6 223.1l.9 .8"/>
<path d="M183.5 223.9l1.1-1.1h1.9l-3 3zM183.6 237.3l14.2-14.3 6.7 6.7-14.2 14.3zM183.7 221.9v-1.8l-2.9 3h1.8l1.1-1.2 .9 .9M183.7 220.1l2.8 2.7M186.9 236l1.2-1.2 .9 .8 .8-.8 3 3-.9 .8 .9 .8-1.3 1.3zM189 233.9l5.5-5.5 4.7 4.7-5.5 5.5zM189 233.9l-.9 .9M191.7 234l.2 2.1 .6 .2 .3-.4-.1-.5 .1-.2 .3 .4-.1 .6-.5 .4-.4-.1-.4-.3-.2-1.7-.7 .8-.2-.2zM192.4 233.2l.7-.2 .6 .4 .7 .9-.1 .6-.7 .3-.8-.4-.6-.9zM192.6 233.4l.6-.1 .6 .5 .4 .5-.2 .5-.5 .2-.6-.4-.4-.7zM193.4 232.3l.1-.1 .4 .4 .8-.8 .5 2.2-1.2-1.1-.2 .2-.2-.2 .2-.2zM193.7 238.6l-.9 .8"/>
<path d="M194.1 232.8l.5-.6 .2 1.3zM195 230.6l.7-.2 .9 .6 .4 .8-.3 .7-.6 .1-.9-.7-.4-.7zM195.2 230.7h.6l.7 .5 .3 .6-.2 .4-.6 .1-.5-.4-.4-.6zM195.3 227.5l1.3-1.2 4.7 4.7-1.3 1.2-.8-.8-.9 .8-3-2.9 .9-.9zM195.3 227.5l-.8 .9M200 232.2l-.8 .9M209.4 222.3v.3M210.7 220.9a1.81 1.81 0 0 0-2.5-.8 1.81 1.81 0 0 0-.7 2.5 1.81 1.81 0 0 0 2.5 .7M210.8 220.9h.3M210.9 220.8l-1.7 1.6 4.7 4.7 .1-.1M213.7 227h.3M215.4 225.6l-1.4 1.4"/>
<path d="M215.5 225.3v.3M215.6 225.4l-.2 .2M219.4 236.4a41.3 41.3 0 0 1-42.4 16.2M220.5 220.2h.3M222.7 231h-3.3v5.4M222.7 231l-3.3 5.4M76.2 243.4h10.4v10.4h-10.4zM91.4 243.4h10.4v10.4h-10.4zM106.7 243.4h10.4v10.4h-10.4zM172.2 247.9l-2.4 2.4 3.9 1.4 3.3 .9M87.7 265h18"/>
<circle cx="91.7" cy="63" r=".6"/>
<circle cx="98.3" cy="75.5" r=".71"/>
<circle cx="106.4" cy="69.9" r=".71"/>
<circle cx="111.2" cy="78.3" r=".3"/>
<circle cx="111.2" cy="79.5" r=".3"/>
<circle cx="113.8" cy="60.5" r=".6"/>
<circle cx="116.9" cy="77.5" r=".6"/>
<circle cx="117.1" cy="74" r=".71"/>
<circle cx="118.9" cy="61.4" r=".71"/>
<circle cx="122.2" cy="75.6" r=".71"/>
<circle cx="122.2" cy="66.8" r=".6"/>
<circle cx="125.2" cy="77.9" r=".71"/>
<circle cx="129.2" cy="79.7" r=".71"/>
<circle cx="133.4" cy="77.1" r=".3"/>
<circle cx="134.6" cy="77.1" r=".3"/>
<circle cx="136.9" cy="70.1" r=".6"/>
<circle cx="138.7" cy="76.2" r=".71"/>
<circle cx="140.4" cy="71.4" r=".71"/>
<circle cx="145.9" cy="79.6" r=".6"/>
<circle cx="146" cy="68" r=".6"/>
<circle cx="146.5" cy="61.5" r=".71"/>
<circle cx="149.4" cy="75.5" r=".3"/>
<circle cx="149.4" cy="76.8" r=".3"/>
<circle cx="157.2" cy="68.5" r=".71"/>
<circle cx="160" cy="73.8" r=".6"/>
<circle cx="164.7" cy="77.7" r=".6"/>
<circle cx="166.4" cy="60.6" r=".71"/>
<circle cx="191.8" cy="78.7" r=".71"/>
<circle cx="208.3" cy="68.4" r="5.6"/>
<circle cx="66.4" cy="99.9" r="5.6"/>
<circle cx="82.7" cy="99.1" r=".71"/>
<circle cx="90.3" cy="82.4" r=".3"/>
<circle cx="91.5" cy="82.4" r=".3"/>
<circle cx="103.7" cy="80.1" r=".22"/>
<circle cx="103.9" cy="83.3" r=".46"/>
<circle cx="103.9" cy="83.3" r=".56"/>
<circle cx="112.8" cy="92" r=".71"/>
<circle cx="113.5" cy="85.3" r=".71"/>
<circle cx="134.1" cy="80.3" r=".71"/>
<circle cx="134.4" cy="83.9" r=".71"/>
<circle cx="135.9" cy="92.4" r=".71"/>
<circle cx="136.1" cy="87.4" r=".6"/>
<circle cx="138.5" cy="97.9" r=".6"/>
<circle cx="143.6" cy="93.6" r=".3"/>
<circle cx="143.6" cy="94.8" r=".3"/>
<circle cx="147.9" cy="96.8" r=".6"/>
<circle cx="151.1" cy="98.8" r=".71"/>
<circle cx="164.5" cy="92.3" r=".71"/>
<circle cx="166.8" cy="87.8" r=".3"/>
<circle cx="166.8" cy="86.5" r=".3"/>
<circle cx="170.3" cy="87.2" r=".71"/>
<circle cx="176.4" cy="89.2" r=".6"/>
<circle cx="177.1" cy="95.2" r=".71"/>
<circle cx="177.2" cy="80.7" r=".6"/>
<circle cx="179.6" cy="87.5" r=".71"/>
<circle cx="184.1" cy="92.6" r=".6"/>
<circle cx="194.5" cy="82.4" r=".71"/>
<circle cx="203.6" cy="84.7" r=".6"/>
<circle cx="293.7" cy="93.2" r="1.2"/>
<circle cx="321.7" cy="81.7" r="1.2"/>
<circle cx="332.9" cy="88.4" r="1.41"/>
<circle cx="336.2" cy="98.1" r="1.41"/>
<circle cx="339.9" cy="85.9" r="1.2"/>
<circle cx="80.4" cy="106.9" r=".6"/>
<circle cx="86.9" cy="107.4" r=".6"/>
<circle cx="99.3" cy="107.3" r=".6"/>
<circle cx="106.5" cy="103.8" r=".3"/>
<circle cx="107.8" cy="103.8" r=".3"/>
<circle cx="113.9" cy="104.2" r=".6"/>
<circle cx="116" cy="107.9" r=".3"/>
<circle cx="117.3" cy="107.9" r=".3"/>
<circle cx="121.2" cy="105.4" r=".6"/>
<circle cx="135.6" cy="105.6" r=".71"/>
<circle cx="137.1" cy="101.9" r=".71"/>
<circle cx="141.6" cy="101" r=".3"/>
<circle cx="142.5" cy="103.8" r=".71"/>
<circle cx="142.8" cy="101" r=".3"/>
<circle cx="157.7" cy="106.5" r=".3"/>
<circle cx="158.9" cy="106.5" r=".3"/>
<circle cx="164.3" cy="107.8" r=".71"/>
<circle cx="184.6" cy="103.2" r=".6"/>
<circle cx="321.9" cy="104.9" r="1.2"/>
<circle cx="96.8" cy="128.8" r="1.75"/>
<circle cx="99.6" cy="159.4" r="1.49"/>
<circle cx="310.5" cy="159.4" r=".6"/>
<circle cx="313.9" cy="154.1" r=".71"/>
<circle cx="341" cy="155.7" r=".6"/>
<circle cx="117.7" cy="162.5" r="1.49"/>
<circle cx="224.5" cy="161.1" r="5.6"/>
<circle cx="229.2" cy="177.4" r=".6"/>
<circle cx="232.5" cy="179.4" r=".3"/>
<circle cx="233.4" cy="178.5" r=".29"/>
<circle cx="242.1" cy="173.7" r=".29"/>
<circle cx="242.9" cy="174.6" r=".3"/>
<circle cx="247.4" cy="179.3" r=".3"/>
<circle cx="249.5" cy="163.8" r="1.01"/>
<circle cx="251.1" cy="169.6" r=".3"/>
<circle cx="252.3" cy="169.6" r=".3"/>
<circle cx="254.5" cy="163.8" r="1.01"/>
<circle cx="255.5" cy="173.4" r=".6"/>
<circle cx="259.9" cy="160.5" r=".6"/>
<circle cx="262.5" cy="179.9" r=".71"/>
<circle cx="272.8" cy="166.5" r=".6"/>
<circle cx="277.8" cy="178.7" r=".29"/>
<circle cx="283.6" cy="179.8" r=".71"/>
<circle cx="286.8" cy="160.7" r=".6"/>
<circle cx="286.9" cy="172.3" r=".6"/>
<circle cx="292.4" cy="164.1" r=".71"/>
<circle cx="294.1" cy="168.9" r=".71"/>
<circle cx="295.9" cy="162.8" r=".6"/>
<circle cx="298.4" cy="176.6" r=".71"/>
<circle cx="298.6" cy="172.9" r=".71"/>
<circle cx="303.6" cy="172.4" r=".71"/>
<circle cx="307.6" cy="170.6" r=".71"/>
<circle cx="310.6" cy="168.3" r=".71"/>
<circle cx="315.7" cy="166.6" r=".71"/>
<circle cx="315.8" cy="170.2" r=".6"/>
<circle cx="319.3" cy="177.9" r=".71"/>
<circle cx="326.3" cy="162.6" r=".71"/>
<circle cx="327.4" cy="169.9" r=".6"/>
<circle cx="332.3" cy="164.1" r=".29"/>
<circle cx="334.5" cy="168.2" r=".71"/>
<circle cx="339.7" cy="175" r=".71"/>
<circle cx="345.7" cy="166.2" r="1.01"/>
<circle cx="349.2" cy="169.7" r="1.01"/>
<circle cx="352.8" cy="173.3" r="1.01"/>
<circle cx="356.3" cy="176.8" r="1.01"/>
<circle cx="150.6" cy="197.8" r="1.81"/>
<circle cx="236.7" cy="182.2" r="1.01"/>
<circle cx="240.2" cy="185.7" r="1.01"/>
<circle cx="243.4" cy="189.4" r=".3"/>
<circle cx="244.2" cy="188.6" r=".3"/>
<circle cx="248.1" cy="195.9" r=".6"/>
<circle cx="248.3" cy="180.2" r=".3"/>
<circle cx="253.1" cy="180.2" r=".71"/>
<circle cx="256.4" cy="181.9" r=".6"/>
<circle cx="265.9" cy="181.7" r=".71"/>
<circle cx="269.7" cy="184.1" r=".3"/>
<circle cx="270.9" cy="184.1" r=".3"/>
<circle cx="277.4" cy="197.9" r=".71"/>
<circle cx="281.7" cy="191.5" r=".71"/>
<circle cx="282.1" cy="195.7" r=".6"/>
<circle cx="289" cy="189" r=".71"/>
<circle cx="289" cy="185.3" r=".71"/>
<circle cx="290.3" cy="196.5" r=".71"/>
<circle cx="294.3" cy="190.5" r=".6"/>
<circle cx="295.7" cy="194.6" r=".71"/>
<circle cx="296.7" cy="180" r=".6"/>
<circle cx="296.9" cy="185.1" r=".71"/>
<circle cx="297.2" cy="198.3" r=".71"/>
<circle cx="298.5" cy="190.1" r=".71"/>
<circle cx="299.3" cy="195.3" r=".71"/>
<circle cx="303" cy="195.1" r=".71"/>
<circle cx="306" cy="189.6" r=".6"/>
<circle cx="306.1" cy="183.3" r=".6"/>
<circle cx="311.6" cy="198.1" r=".6"/>
<circle cx="312.2" cy="183.3" r=".6"/>
<circle cx="312.4" cy="189.7" r=".6"/>
<circle cx="318.8" cy="196.9" r=".6"/>
<circle cx="319.9" cy="184.7" r=".71"/>
<circle cx="327" cy="185.8" r=".71"/>
<circle cx="327.5" cy="198.1" r=".6"/>
<circle cx="331.4" cy="188.2" r=".71"/>
<circle cx="335" cy="182.2" r=".71"/>
<circle cx="350.1" cy="191.8" r=".71"/>
<circle cx="352.4" cy="199.6" r=".6"/>
<circle cx="366.4" cy="192.6" r="5.6"/>
<circle cx="173.1" cy="212.2" r="3"/>
<circle cx="222.6" cy="206.3" r="2.11"/>
<circle cx="333.4" cy="200" r=".6"/>
<circle cx="345.9" cy="200.1" r=".6"/>
<circle cx="183.7" cy="222.8" r="3"/>
</g>
<g fill="#000">
<circle cx="103.4" cy="79.1" r=".25"/>
<circle cx="148.8" cy="93.2" r=".25"/>
<circle cx="148.8" cy="89.2" r=".25"/>
<circle cx="148.8" cy="91.3" r=".25"/>
<circle cx="148.8" cy="90.5" r=".25"/>
<circle cx="148.8" cy="87.3" r=".25"/>
<circle cx="151.2" cy="84.8" r=".25"/>
<circle cx="152.4" cy="96.8" r=".25"/>
<circle cx="153.2" cy="96.8" r=".25"/>
<circle cx="153.2" cy="84.8" r=".25"/>
<circle cx="154.4" cy="96.8" r=".25"/>
<circle cx="155.2" cy="96.8" r=".25"/>
<circle cx="155.2" cy="84.8" r=".25"/>
<circle cx="156.4" cy="96.8" r=".25"/>
<circle cx="157.2" cy="84.8" r=".25"/>
<circle cx="158.4" cy="96.8" r=".25"/>
<circle cx="160.8" cy="96.8" r=".25"/>
<circle cx="160.8" cy="93.2" r=".25"/>
<circle cx="160.8" cy="87.3" r=".25"/>
<circle cx="160.8" cy="90.5" r=".25"/>
<circle cx="160.8" cy="91.3" r=".25"/>
<circle cx="160.8" cy="89.2" r=".25"/>
<circle cx="283.9" cy="179.9" r=".25"/>
</g>
<!-- layer: Border -->
<g fill="none" stroke="#000" stroke-width=".28">
<path d="M15 .1h-15v15M20 10.1h390v276.9h-390zM65 5.1v5M115 5.1v5M165 5.1v5M215 5.1v10M265 5.1v5M315 5.1v5M365 5.1v5M405 .1h15v15M15 52.9h5M410 52.9h5"/>
<path d="M15 100.7h5M410 100.7h5M15 148.6h10M405 148.6h10M15 196.4h5M410 196.4h5M15 244.2h5M410 244.2h5M0 282.1v14.9h15M65 287v5M115 287v5M165 287v5"/>
<path d="M215 282.1v9.9M265 287v5M315 287v5M365 287v5M420 282.1v14.9h-15"/>
</g>
<!-- layer: TitleBlock -->
<path d="M230 240.1h180v46.9h-180zM230 250h180M254 240.1v9.9M288 240.1v46.9M349 240.1v46.9M288 260.1h122M349 277.1h61M359 277.1v9.9M395 277.1v9.9" fill="none" stroke="#000" stroke-width=".36"/>
<!-- layer: Annotations -->
<g fill="#000" stroke="#000" stroke-width=".28">
<path d="M169.2 59.1l1.1 .4-1.9 3.1zM98.7 73.7l.9-.7 1.5 3.2zM110.7 71.8l1.2-.1-.5 3.6zM132.9 72.2l1.1-.1-.1 3.5zM146.6 75.8l1.1-.2 .1 3.6zM88.5 83.1l3.4-.9-3 2zM142.1 94.6l-.7 3.5-1.1-.5zM168 88.7l2.8 2.1-.8 .8zM83.8 102.5l-1.5 3.2-.9-.7zM144.5 102.5l.7 3.5h-1.2zM149.2 108.2l.2 3.5-1.2-.1zM158 108.2l1.8 3-1.1 .5z"/>
<path d="M158 102.8l2.9 1.9-.8 .8zM162.9 100.6l3.1 1.8-.8 .9zM86 138.5l3.3-1.5 .2 1.2zM89.1 155.4l3.2-1.6 .3 1.1zM332.5 151.4l1.1-.3 .3 3.6zM94 173.7l3.3-1.1-2.8 2.2zM260.8 160.7l1.1-.4 .7 3.5zM278.2 175.8l2.6-2.4 .7 1zM330.8 167.7l2.3 2.7-1 .6zM193.2 180.5l1.1 .3-1.5 3.2zM204.3 192.8h1.2l-.5 3.5zM272.9 184.2l2.5-2.5 .7 1z"/>
<path d="M285.3 188.6l2.8 2.2-.8 .8zM344.5 188.6l2.3 2.7-1.1 .6zM163.6 207.5l1.1 3.3-1.2 .2zM187.2 229.8l3.5 .4-3.4 .7zM218.1 222.9l3.4 1.1-.5 1z"/>
</g>
<g fill="none" stroke="#000" stroke-width=".28">
<path d="M43.5 36.1h30.1l25.5 37.2M124.9 49.1h17.4l4.9 26.6M217.5 44.2h-41.8l-6 15.1M102 62.4h9l.3 9.3M118.3 67.8h14.6l.5 4.4M88.7 83.7l-34.2 15.3h-25.9M119.3 84.9l-1.8 3.8M140.9 97.8l-5.9 15h-13.1M170.4 91.2l28.4 29.3h11.6M81.9 105.4l-13.9 20.1h-20.7M144.6 106l.2 13.9h-11.7M148.8 111.7l-2.3 18.4h30.3"/>
<path d="M159.2 111.4l3.7 9.7h14.6M160.5 105.1l6.8 6.3h15.6M165.6 102.8l2.8 2.3h11.2M118 134.4h-16l-12.6 3.2M307 129.9l-5.3 6.1M405 137.9h-75.3l3.4 13.4M116.8 149.4h-8.9l-15.4 4.9M236.4 142.8h18.2l6.7 17.8M94.3 174.3l-18 9.6h-14.6M200.6 166.1h3.5l.8 26.7M209.3 166.1h-11.6l-4 14.6M223.3 178.4l4.1 .9"/>
<path d="M236.4 166h13.2l3.2 2.4M296 170.3h-9.4l-5.4 3.6M296.2 178.3h-14.5l-5.9 3.9M332.6 170.7l4.8 7.7h8.9M287.7 191.2l4.4 4.6h13.9M346.2 191.6l14.2 25.1h18.5M164.1 210.9l3.3 20.3h3.5M266.4 207.7l1.5 4.6M187.2 230.3l-18.5 .9h-13.4M221.2 224.5l7.7 4h21.6"/>
<circle cx="112" cy="100.1" r="12.6"/>
<circle cx="286.6" cy="153.5" r="23.1"/>
<circle cx="240.9" cy="182.2" r="13.8"/>
<circle cx="262.3" cy="195" r="13.3"/>
</g>
<use href="#words"/>
</svg>
